VERSION 5.7 ;
BUSBITCHARS "[]" ;
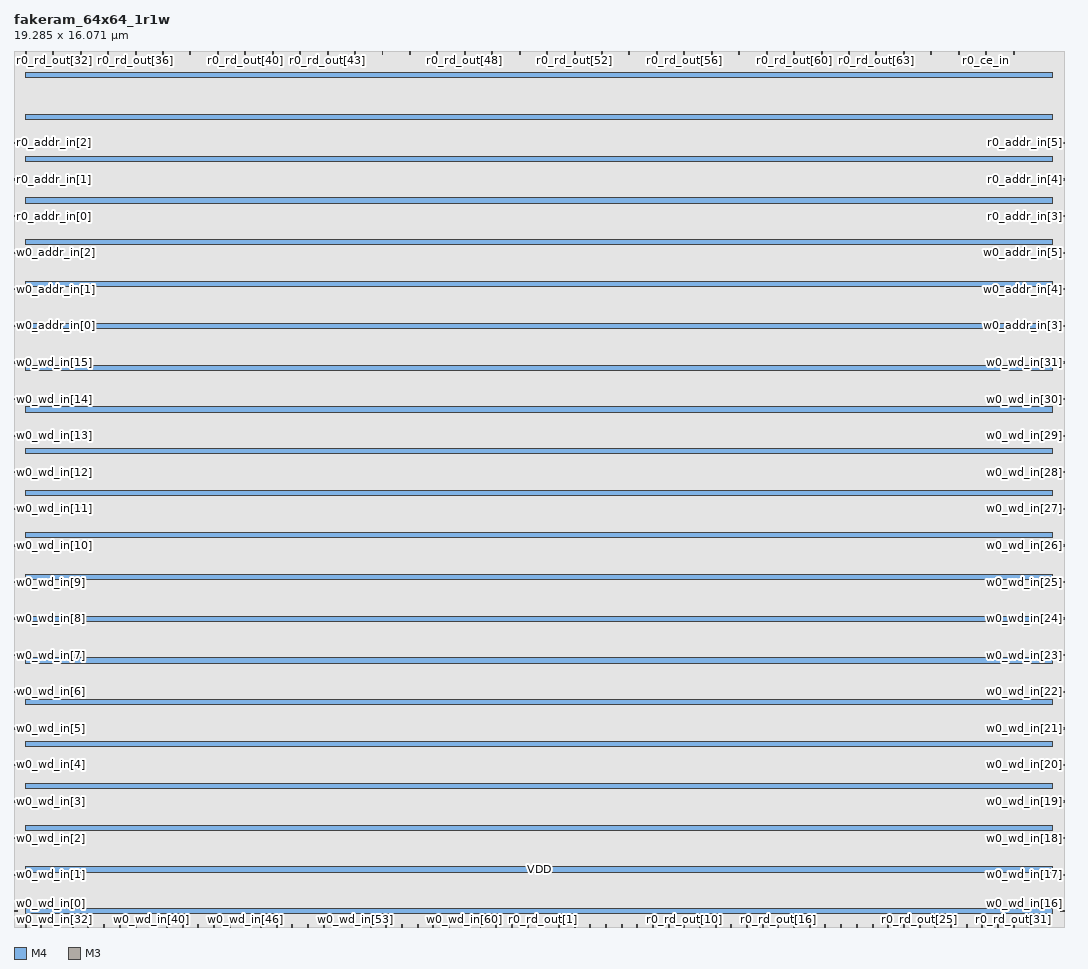
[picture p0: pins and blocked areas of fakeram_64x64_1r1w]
MACRO fakeram_64x64_1r1w
  FOREIGN fakeram_64x64_1r1w 0 0 ;
  SYMMETRY X Y R90 ;
  SIZE 19.285 BY 16.071 ;
  CLASS BLOCK ;
  PIN w0_wd_in[0]
    DIRECTION INPUT ;
    USE SIGNAL ;
    SHAPE ABUTMENT ;
    PORT
      LAYER M4 ;
      RECT 0.000 0.276 0.072 0.300 ;
    END
  END w0_wd_in[0]
  PIN w0_wd_in[1]
    DIRECTION INPUT ;
    USE SIGNAL ;
    SHAPE ABUTMENT ;
    PORT
      LAYER M4 ;
      RECT 0.000 0.948 0.072 0.972 ;
    END
  END w0_wd_in[1]
  PIN w0_wd_in[2]
    DIRECTION INPUT ;
    USE SIGNAL ;
    SHAPE ABUTMENT ;
    PORT
      LAYER M4 ;
      RECT 0.000 1.620 0.072 1.644 ;
    END
  END w0_wd_in[2]
  PIN w0_wd_in[3]
    DIRECTION INPUT ;
    USE SIGNAL ;
    SHAPE ABUTMENT ;
    PORT
      LAYER M4 ;
      RECT 0.000 2.292 0.072 2.316 ;
    END
  END w0_wd_in[3]
  PIN w0_wd_in[4]
    DIRECTION INPUT ;
    USE SIGNAL ;
    SHAPE ABUTMENT ;
    PORT
      LAYER M4 ;
      RECT 0.000 2.964 0.072 2.988 ;
    END
  END w0_wd_in[4]
  PIN w0_wd_in[5]
    DIRECTION INPUT ;
    USE SIGNAL ;
    SHAPE ABUTMENT ;
    PORT
      LAYER M4 ;
      RECT 0.000 3.636 0.072 3.660 ;
    END
  END w0_wd_in[5]
  PIN w0_wd_in[6]
    DIRECTION INPUT ;
    USE SIGNAL ;
    SHAPE ABUTMENT ;
    PORT
      LAYER M4 ;
      RECT 0.000 4.308 0.072 4.332 ;
    END
  END w0_wd_in[6]
  PIN w0_wd_in[7]
    DIRECTION INPUT ;
    USE SIGNAL ;
    SHAPE ABUTMENT ;
    PORT
      LAYER M4 ;
      RECT 0.000 4.980 0.072 5.004 ;
    END
  END w0_wd_in[7]
  PIN w0_wd_in[8]
    DIRECTION INPUT ;
    USE SIGNAL ;
    SHAPE ABUTMENT ;
    PORT
      LAYER M4 ;
      RECT 0.000 5.652 0.072 5.676 ;
    END
  END w0_wd_in[8]
  PIN w0_wd_in[9]
    DIRECTION INPUT ;
    USE SIGNAL ;
    SHAPE ABUTMENT ;
    PORT
      LAYER M4 ;
      RECT 0.000 6.324 0.072 6.348 ;
    END
  END w0_wd_in[9]
  PIN w0_wd_in[10]
    DIRECTION INPUT ;
    USE SIGNAL ;
    SHAPE ABUTMENT ;
    PORT
      LAYER M4 ;
      RECT 0.000 6.996 0.072 7.020 ;
    END
  END w0_wd_in[10]
  PIN w0_wd_in[11]
    DIRECTION INPUT ;
    USE SIGNAL ;
    SHAPE ABUTMENT ;
    PORT
      LAYER M4 ;
      RECT 0.000 7.668 0.072 7.692 ;
    END
  END w0_wd_in[11]
  PIN w0_wd_in[12]
    DIRECTION INPUT ;
    USE SIGNAL ;
    SHAPE ABUTMENT ;
    PORT
      LAYER M4 ;
      RECT 0.000 8.340 0.072 8.364 ;
    END
  END w0_wd_in[12]
  PIN w0_wd_in[13]
    DIRECTION INPUT ;
    USE SIGNAL ;
    SHAPE ABUTMENT ;
    PORT
      LAYER M4 ;
      RECT 0.000 9.012 0.072 9.036 ;
    END
  END w0_wd_in[13]
  PIN w0_wd_in[14]
    DIRECTION INPUT ;
    USE SIGNAL ;
    SHAPE ABUTMENT ;
    PORT
      LAYER M4 ;
      RECT 0.000 9.684 0.072 9.708 ;
    END
  END w0_wd_in[14]
  PIN w0_wd_in[15]
    DIRECTION INPUT ;
    USE SIGNAL ;
    SHAPE ABUTMENT ;
    PORT
      LAYER M4 ;
      RECT 0.000 10.356 0.072 10.380 ;
    END
  END w0_wd_in[15]
  PIN w0_wd_in[16]
    DIRECTION INPUT ;
    USE SIGNAL ;
    SHAPE ABUTMENT ;
    PORT
      LAYER M4 ;
      RECT 19.213 0.276 19.285 0.300 ;
    END
  END w0_wd_in[16]
  PIN w0_wd_in[17]
    DIRECTION INPUT ;
    USE SIGNAL ;
    SHAPE ABUTMENT ;
    PORT
      LAYER M4 ;
      RECT 19.213 0.948 19.285 0.972 ;
    END
  END w0_wd_in[17]
  PIN w0_wd_in[18]
    DIRECTION INPUT ;
    USE SIGNAL ;
    SHAPE ABUTMENT ;
    PORT
      LAYER M4 ;
      RECT 19.213 1.620 19.285 1.644 ;
    END
  END w0_wd_in[18]
  PIN w0_wd_in[19]
    DIRECTION INPUT ;
    USE SIGNAL ;
    SHAPE ABUTMENT ;
    PORT
      LAYER M4 ;
      RECT 19.213 2.292 19.285 2.316 ;
    END
  END w0_wd_in[19]
  PIN w0_wd_in[20]
    DIRECTION INPUT ;
    USE SIGNAL ;
    SHAPE ABUTMENT ;
    PORT
      LAYER M4 ;
      RECT 19.213 2.964 19.285 2.988 ;
    END
  END w0_wd_in[20]
  PIN w0_wd_in[21]
    DIRECTION INPUT ;
    USE SIGNAL ;
    SHAPE ABUTMENT ;
    PORT
      LAYER M4 ;
      RECT 19.213 3.636 19.285 3.660 ;
    END
  END w0_wd_in[21]
  PIN w0_wd_in[22]
    DIRECTION INPUT ;
    USE SIGNAL ;
    SHAPE ABUTMENT ;
    PORT
      LAYER M4 ;
      RECT 19.213 4.308 19.285 4.332 ;
    END
  END w0_wd_in[22]
  PIN w0_wd_in[23]
    DIRECTION INPUT ;
    USE SIGNAL ;
    SHAPE ABUTMENT ;
    PORT
      LAYER M4 ;
      RECT 19.213 4.980 19.285 5.004 ;
    END
  END w0_wd_in[23]
  PIN w0_wd_in[24]
    DIRECTION INPUT ;
    USE SIGNAL ;
    SHAPE ABUTMENT ;
    PORT
      LAYER M4 ;
      RECT 19.213 5.652 19.285 5.676 ;
    END
  END w0_wd_in[24]
  PIN w0_wd_in[25]
    DIRECTION INPUT ;
    USE SIGNAL ;
    SHAPE ABUTMENT ;
    PORT
      LAYER M4 ;
      RECT 19.213 6.324 19.285 6.348 ;
    END
  END w0_wd_in[25]
  PIN w0_wd_in[26]
    DIRECTION INPUT ;
    USE SIGNAL ;
    SHAPE ABUTMENT ;
    PORT
      LAYER M4 ;
      RECT 19.213 6.996 19.285 7.020 ;
    END
  END w0_wd_in[26]
  PIN w0_wd_in[27]
    DIRECTION INPUT ;
    USE SIGNAL ;
    SHAPE ABUTMENT ;
    PORT
      LAYER M4 ;
      RECT 19.213 7.668 19.285 7.692 ;
    END
  END w0_wd_in[27]
  PIN w0_wd_in[28]
    DIRECTION INPUT ;
    USE SIGNAL ;
    SHAPE ABUTMENT ;
    PORT
      LAYER M4 ;
      RECT 19.213 8.340 19.285 8.364 ;
    END
  END w0_wd_in[28]
  PIN w0_wd_in[29]
    DIRECTION INPUT ;
    USE SIGNAL ;
    SHAPE ABUTMENT ;
    PORT
      LAYER M4 ;
      RECT 19.213 9.012 19.285 9.036 ;
    END
  END w0_wd_in[29]
  PIN w0_wd_in[30]
    DIRECTION INPUT ;
    USE SIGNAL ;
    SHAPE ABUTMENT ;
    PORT
      LAYER M4 ;
      RECT 19.213 9.684 19.285 9.708 ;
    END
  END w0_wd_in[30]
  PIN w0_wd_in[31]
    DIRECTION INPUT ;
    USE SIGNAL ;
    SHAPE ABUTMENT ;
    PORT
      LAYER M4 ;
      RECT 19.213 10.356 19.285 10.380 ;
    END
  END w0_wd_in[31]
  PIN w0_wd_in[32]
    DIRECTION OUTPUT ;
    USE SIGNAL ;
    SHAPE ABUTMENT ;
    PORT
      LAYER M3 ;
      RECT 0.207 0.000 0.225 0.054 ;
    END
  END w0_wd_in[32]
  PIN w0_wd_in[33]
    DIRECTION OUTPUT ;
    USE SIGNAL ;
    SHAPE ABUTMENT ;
    PORT
      LAYER M3 ;
      RECT 0.495 0.000 0.513 0.054 ;
    END
  END w0_wd_in[33]
  PIN w0_wd_in[34]
    DIRECTION OUTPUT ;
    USE SIGNAL ;
    SHAPE ABUTMENT ;
    PORT
      LAYER M3 ;
      RECT 0.783 0.000 0.801 0.054 ;
    END
  END w0_wd_in[34]
  PIN w0_wd_in[35]
    DIRECTION OUTPUT ;
    USE SIGNAL ;
    SHAPE ABUTMENT ;
    PORT
      LAYER M3 ;
      RECT 1.071 0.000 1.089 0.054 ;
    END
  END w0_wd_in[35]
  PIN w0_wd_in[36]
    DIRECTION OUTPUT ;
    USE SIGNAL ;
    SHAPE ABUTMENT ;
    PORT
      LAYER M3 ;
      RECT 1.359 0.000 1.377 0.054 ;
    END
  END w0_wd_in[36]
  PIN w0_wd_in[37]
    DIRECTION OUTPUT ;
    USE SIGNAL ;
    SHAPE ABUTMENT ;
    PORT
      LAYER M3 ;
      RECT 1.647 0.000 1.665 0.054 ;
    END
  END w0_wd_in[37]
  PIN w0_wd_in[38]
    DIRECTION OUTPUT ;
    USE SIGNAL ;
    SHAPE ABUTMENT ;
    PORT
      LAYER M3 ;
      RECT 1.935 0.000 1.953 0.054 ;
    END
  END w0_wd_in[38]
  PIN w0_wd_in[39]
    DIRECTION OUTPUT ;
    USE SIGNAL ;
    SHAPE ABUTMENT ;
    PORT
      LAYER M3 ;
      RECT 2.223 0.000 2.241 0.054 ;
    END
  END w0_wd_in[39]
  PIN w0_wd_in[40]
    DIRECTION OUTPUT ;
    USE SIGNAL ;
    SHAPE ABUTMENT ;
    PORT
      LAYER M3 ;
      RECT 2.511 0.000 2.529 0.054 ;
    END
  END w0_wd_in[40]
  PIN w0_wd_in[41]
    DIRECTION OUTPUT ;
    USE SIGNAL ;
    SHAPE ABUTMENT ;
    PORT
      LAYER M3 ;
      RECT 2.799 0.000 2.817 0.054 ;
    END
  END w0_wd_in[41]
  PIN w0_wd_in[42]
    DIRECTION OUTPUT ;
    USE SIGNAL ;
    SHAPE ABUTMENT ;
    PORT
      LAYER M3 ;
      RECT 3.087 0.000 3.105 0.054 ;
    END
  END w0_wd_in[42]
  PIN w0_wd_in[43]
    DIRECTION OUTPUT ;
    USE SIGNAL ;
    SHAPE ABUTMENT ;
    PORT
      LAYER M3 ;
      RECT 3.375 0.000 3.393 0.054 ;
    END
  END w0_wd_in[43]
  PIN w0_wd_in[44]
    DIRECTION OUTPUT ;
    USE SIGNAL ;
    SHAPE ABUTMENT ;
    PORT
      LAYER M3 ;
      RECT 3.663 0.000 3.681 0.054 ;
    END
  END w0_wd_in[44]
  PIN w0_wd_in[45]
    DIRECTION OUTPUT ;
    USE SIGNAL ;
    SHAPE ABUTMENT ;
    PORT
      LAYER M3 ;
      RECT 3.951 0.000 3.969 0.054 ;
    END
  END w0_wd_in[45]
  PIN w0_wd_in[46]
    DIRECTION OUTPUT ;
    USE SIGNAL ;
    SHAPE ABUTMENT ;
    PORT
      LAYER M3 ;
      RECT 4.239 0.000 4.257 0.054 ;
    END
  END w0_wd_in[46]
  PIN w0_wd_in[47]
    DIRECTION OUTPUT ;
    USE SIGNAL ;
    SHAPE ABUTMENT ;
    PORT
      LAYER M3 ;
      RECT 4.527 0.000 4.545 0.054 ;
    END
  END w0_wd_in[47]
  PIN w0_wd_in[48]
    DIRECTION OUTPUT ;
    USE SIGNAL ;
    SHAPE ABUTMENT ;
    PORT
      LAYER M3 ;
      RECT 4.815 0.000 4.833 0.054 ;
    END
  END w0_wd_in[48]
  PIN w0_wd_in[49]
    DIRECTION OUTPUT ;
    USE SIGNAL ;
    SHAPE ABUTMENT ;
    PORT
      LAYER M3 ;
      RECT 5.103 0.000 5.121 0.054 ;
    END
  END w0_wd_in[49]
  PIN w0_wd_in[50]
    DIRECTION OUTPUT ;
    USE SIGNAL ;
    SHAPE ABUTMENT ;
    PORT
      LAYER M3 ;
      RECT 5.391 0.000 5.409 0.054 ;
    END
  END w0_wd_in[50]
  PIN w0_wd_in[51]
    DIRECTION OUTPUT ;
    USE SIGNAL ;
    SHAPE ABUTMENT ;
    PORT
      LAYER M3 ;
      RECT 5.679 0.000 5.697 0.054 ;
    END
  END w0_wd_in[51]
  PIN w0_wd_in[52]
    DIRECTION OUTPUT ;
    USE SIGNAL ;
    SHAPE ABUTMENT ;
    PORT
      LAYER M3 ;
      RECT 5.967 0.000 5.985 0.054 ;
    END
  END w0_wd_in[52]
  PIN w0_wd_in[53]
    DIRECTION OUTPUT ;
    USE SIGNAL ;
    SHAPE ABUTMENT ;
    PORT
      LAYER M3 ;
      RECT 6.255 0.000 6.273 0.054 ;
    END
  END w0_wd_in[53]
  PIN w0_wd_in[54]
    DIRECTION OUTPUT ;
    USE SIGNAL ;
    SHAPE ABUTMENT ;
    PORT
      LAYER M3 ;
      RECT 6.543 0.000 6.561 0.054 ;
    END
  END w0_wd_in[54]
  PIN w0_wd_in[55]
    DIRECTION OUTPUT ;
    USE SIGNAL ;
    SHAPE ABUTMENT ;
    PORT
      LAYER M3 ;
      RECT 6.831 0.000 6.849 0.054 ;
    END
  END w0_wd_in[55]
  PIN w0_wd_in[56]
    DIRECTION OUTPUT ;
    USE SIGNAL ;
    SHAPE ABUTMENT ;
    PORT
      LAYER M3 ;
      RECT 7.119 0.000 7.137 0.054 ;
    END
  END w0_wd_in[56]
  PIN w0_wd_in[57]
    DIRECTION OUTPUT ;
    USE SIGNAL ;
    SHAPE ABUTMENT ;
    PORT
      LAYER M3 ;
      RECT 7.407 0.000 7.425 0.054 ;
    END
  END w0_wd_in[57]
  PIN w0_wd_in[58]
    DIRECTION OUTPUT ;
    USE SIGNAL ;
    SHAPE ABUTMENT ;
    PORT
      LAYER M3 ;
      RECT 7.695 0.000 7.713 0.054 ;
    END
  END w0_wd_in[58]
  PIN w0_wd_in[59]
    DIRECTION OUTPUT ;
    USE SIGNAL ;
    SHAPE ABUTMENT ;
    PORT
      LAYER M3 ;
      RECT 7.983 0.000 8.001 0.054 ;
    END
  END w0_wd_in[59]
  PIN w0_wd_in[60]
    DIRECTION OUTPUT ;
    USE SIGNAL ;
    SHAPE ABUTMENT ;
    PORT
      LAYER M3 ;
      RECT 8.271 0.000 8.289 0.054 ;
    END
  END w0_wd_in[60]
  PIN w0_wd_in[61]
    DIRECTION OUTPUT ;
    USE SIGNAL ;
    SHAPE ABUTMENT ;
    PORT
      LAYER M3 ;
      RECT 8.559 0.000 8.577 0.054 ;
    END
  END w0_wd_in[61]
  PIN w0_wd_in[62]
    DIRECTION OUTPUT ;
    USE SIGNAL ;
    SHAPE ABUTMENT ;
    PORT
      LAYER M3 ;
      RECT 8.847 0.000 8.865 0.054 ;
    END
  END w0_wd_in[62]
  PIN w0_wd_in[63]
    DIRECTION OUTPUT ;
    USE SIGNAL ;
    SHAPE ABUTMENT ;
    PORT
      LAYER M3 ;
      RECT 9.135 0.000 9.153 0.054 ;
    END
  END w0_wd_in[63]
  PIN r0_rd_out[0]
    DIRECTION OUTPUT ;
    USE SIGNAL ;
    SHAPE ABUTMENT ;
    PORT
      LAYER M3 ;
      RECT 9.423 0.000 9.441 0.054 ;
    END
  END r0_rd_out[0]
  PIN r0_rd_out[1]
    DIRECTION OUTPUT ;
    USE SIGNAL ;
    SHAPE ABUTMENT ;
    PORT
      LAYER M3 ;
      RECT 9.711 0.000 9.729 0.054 ;
    END
  END r0_rd_out[1]
  PIN r0_rd_out[2]
    DIRECTION OUTPUT ;
    USE SIGNAL ;
    SHAPE ABUTMENT ;
    PORT
      LAYER M3 ;
      RECT 9.999 0.000 10.017 0.054 ;
    END
  END r0_rd_out[2]
  PIN r0_rd_out[3]
    DIRECTION OUTPUT ;
    USE SIGNAL ;
    SHAPE ABUTMENT ;
    PORT
      LAYER M3 ;
      RECT 10.287 0.000 10.305 0.054 ;
    END
  END r0_rd_out[3]
  PIN r0_rd_out[4]
    DIRECTION OUTPUT ;
    USE SIGNAL ;
    SHAPE ABUTMENT ;
    PORT
      LAYER M3 ;
      RECT 10.575 0.000 10.593 0.054 ;
    END
  END r0_rd_out[4]
  PIN r0_rd_out[5]
    DIRECTION OUTPUT ;
    USE SIGNAL ;
    SHAPE ABUTMENT ;
    PORT
      LAYER M3 ;
      RECT 10.863 0.000 10.881 0.054 ;
    END
  END r0_rd_out[5]
  PIN r0_rd_out[6]
    DIRECTION OUTPUT ;
    USE SIGNAL ;
    SHAPE ABUTMENT ;
    PORT
      LAYER M3 ;
      RECT 11.151 0.000 11.169 0.054 ;
    END
  END r0_rd_out[6]
  PIN r0_rd_out[7]
    DIRECTION OUTPUT ;
    USE SIGNAL ;
    SHAPE ABUTMENT ;
    PORT
      LAYER M3 ;
      RECT 11.439 0.000 11.457 0.054 ;
    END
  END r0_rd_out[7]
  PIN r0_rd_out[8]
    DIRECTION OUTPUT ;
    USE SIGNAL ;
    SHAPE ABUTMENT ;
    PORT
      LAYER M3 ;
      RECT 11.727 0.000 11.745 0.054 ;
    END
  END r0_rd_out[8]
  PIN r0_rd_out[9]
    DIRECTION OUTPUT ;
    USE SIGNAL ;
    SHAPE ABUTMENT ;
    PORT
      LAYER M3 ;
      RECT 12.015 0.000 12.033 0.054 ;
    END
  END r0_rd_out[9]
  PIN r0_rd_out[10]
    DIRECTION OUTPUT ;
    USE SIGNAL ;
    SHAPE ABUTMENT ;
    PORT
      LAYER M3 ;
      RECT 12.303 0.000 12.321 0.054 ;
    END
  END r0_rd_out[10]
  PIN r0_rd_out[11]
    DIRECTION OUTPUT ;
    USE SIGNAL ;
    SHAPE ABUTMENT ;
    PORT
      LAYER M3 ;
      RECT 12.591 0.000 12.609 0.054 ;
    END
  END r0_rd_out[11]
  PIN r0_rd_out[12]
    DIRECTION OUTPUT ;
    USE SIGNAL ;
    SHAPE ABUTMENT ;
    PORT
      LAYER M3 ;
      RECT 12.879 0.000 12.897 0.054 ;
    END
  END r0_rd_out[12]
  PIN r0_rd_out[13]
    DIRECTION OUTPUT ;
    USE SIGNAL ;
    SHAPE ABUTMENT ;
    PORT
      LAYER M3 ;
      RECT 13.167 0.000 13.185 0.054 ;
    END
  END r0_rd_out[13]
  PIN r0_rd_out[14]
    DIRECTION OUTPUT ;
    USE SIGNAL ;
    SHAPE ABUTMENT ;
    PORT
      LAYER M3 ;
      RECT 13.455 0.000 13.473 0.054 ;
    END
  END r0_rd_out[14]
  PIN r0_rd_out[15]
    DIRECTION OUTPUT ;
    USE SIGNAL ;
    SHAPE ABUTMENT ;
    PORT
      LAYER M3 ;
      RECT 13.743 0.000 13.761 0.054 ;
    END
  END r0_rd_out[15]
  PIN r0_rd_out[16]
    DIRECTION OUTPUT ;
    USE SIGNAL ;
    SHAPE ABUTMENT ;
    PORT
      LAYER M3 ;
      RECT 14.031 0.000 14.049 0.054 ;
    END
  END r0_rd_out[16]
  PIN r0_rd_out[17]
    DIRECTION OUTPUT ;
    USE SIGNAL ;
    SHAPE ABUTMENT ;
    PORT
      LAYER M3 ;
      RECT 14.319 0.000 14.337 0.054 ;
    END
  END r0_rd_out[17]
  PIN r0_rd_out[18]
    DIRECTION OUTPUT ;
    USE SIGNAL ;
    SHAPE ABUTMENT ;
    PORT
      LAYER M3 ;
      RECT 14.607 0.000 14.625 0.054 ;
    END
  END r0_rd_out[18]
  PIN r0_rd_out[19]
    DIRECTION OUTPUT ;
    USE SIGNAL ;
    SHAPE ABUTMENT ;
    PORT
      LAYER M3 ;
      RECT 14.895 0.000 14.913 0.054 ;
    END
  END r0_rd_out[19]
  PIN r0_rd_out[20]
    DIRECTION OUTPUT ;
    USE SIGNAL ;
    SHAPE ABUTMENT ;
    PORT
      LAYER M3 ;
      RECT 15.183 0.000 15.201 0.054 ;
    END
  END r0_rd_out[20]
  PIN r0_rd_out[21]
    DIRECTION OUTPUT ;
    USE SIGNAL ;
    SHAPE ABUTMENT ;
    PORT
      LAYER M3 ;
      RECT 15.471 0.000 15.489 0.054 ;
    END
  END r0_rd_out[21]
  PIN r0_rd_out[22]
    DIRECTION OUTPUT ;
    USE SIGNAL ;
    SHAPE ABUTMENT ;
    PORT
      LAYER M3 ;
      RECT 15.759 0.000 15.777 0.054 ;
    END
  END r0_rd_out[22]
  PIN r0_rd_out[23]
    DIRECTION OUTPUT ;
    USE SIGNAL ;
    SHAPE ABUTMENT ;
    PORT
      LAYER M3 ;
      RECT 16.047 0.000 16.065 0.054 ;
    END
  END r0_rd_out[23]
  PIN r0_rd_out[24]
    DIRECTION OUTPUT ;
    USE SIGNAL ;
    SHAPE ABUTMENT ;
    PORT
      LAYER M3 ;
      RECT 16.335 0.000 16.353 0.054 ;
    END
  END r0_rd_out[24]
  PIN r0_rd_out[25]
    DIRECTION OUTPUT ;
    USE SIGNAL ;
    SHAPE ABUTMENT ;
    PORT
      LAYER M3 ;
      RECT 16.623 0.000 16.641 0.054 ;
    END
  END r0_rd_out[25]
  PIN r0_rd_out[26]
    DIRECTION OUTPUT ;
    USE SIGNAL ;
    SHAPE ABUTMENT ;
    PORT
      LAYER M3 ;
      RECT 16.911 0.000 16.929 0.054 ;
    END
  END r0_rd_out[26]
  PIN r0_rd_out[27]
    DIRECTION OUTPUT ;
    USE SIGNAL ;
    SHAPE ABUTMENT ;
    PORT
      LAYER M3 ;
      RECT 17.199 0.000 17.217 0.054 ;
    END
  END r0_rd_out[27]
  PIN r0_rd_out[28]
    DIRECTION OUTPUT ;
    USE SIGNAL ;
    SHAPE ABUTMENT ;
    PORT
      LAYER M3 ;
      RECT 17.487 0.000 17.505 0.054 ;
    END
  END r0_rd_out[28]
  PIN r0_rd_out[29]
    DIRECTION OUTPUT ;
    USE SIGNAL ;
    SHAPE ABUTMENT ;
    PORT
      LAYER M3 ;
      RECT 17.775 0.000 17.793 0.054 ;
    END
  END r0_rd_out[29]
  PIN r0_rd_out[30]
    DIRECTION OUTPUT ;
    USE SIGNAL ;
    SHAPE ABUTMENT ;
    PORT
      LAYER M3 ;
      RECT 18.063 0.000 18.081 0.054 ;
    END
  END r0_rd_out[30]
  PIN r0_rd_out[31]
    DIRECTION OUTPUT ;
    USE SIGNAL ;
    SHAPE ABUTMENT ;
    PORT
      LAYER M3 ;
      RECT 18.351 0.000 18.369 0.054 ;
    END
  END r0_rd_out[31]
  PIN r0_rd_out[32]
    DIRECTION OUTPUT ;
    USE SIGNAL ;
    SHAPE ABUTMENT ;
    PORT
      LAYER M3 ;
      RECT 0.207 16.017 0.225 16.071 ;
    END
  END r0_rd_out[32]
  PIN r0_rd_out[33]
    DIRECTION OUTPUT ;
    USE SIGNAL ;
    SHAPE ABUTMENT ;
    PORT
      LAYER M3 ;
      RECT 0.711 16.017 0.729 16.071 ;
    END
  END r0_rd_out[33]
  PIN r0_rd_out[34]
    DIRECTION OUTPUT ;
    USE SIGNAL ;
    SHAPE ABUTMENT ;
    PORT
      LAYER M3 ;
      RECT 1.215 16.017 1.233 16.071 ;
    END
  END r0_rd_out[34]
  PIN r0_rd_out[35]
    DIRECTION OUTPUT ;
    USE SIGNAL ;
    SHAPE ABUTMENT ;
    PORT
      LAYER M3 ;
      RECT 1.719 16.017 1.737 16.071 ;
    END
  END r0_rd_out[35]
  PIN r0_rd_out[36]
    DIRECTION OUTPUT ;
    USE SIGNAL ;
    SHAPE ABUTMENT ;
    PORT
      LAYER M3 ;
      RECT 2.223 16.017 2.241 16.071 ;
    END
  END r0_rd_out[36]
  PIN r0_rd_out[37]
    DIRECTION OUTPUT ;
    USE SIGNAL ;
    SHAPE ABUTMENT ;
    PORT
      LAYER M3 ;
      RECT 2.727 16.017 2.745 16.071 ;
    END
  END r0_rd_out[37]
  PIN r0_rd_out[38]
    DIRECTION OUTPUT ;
    USE SIGNAL ;
    SHAPE ABUTMENT ;
    PORT
      LAYER M3 ;
      RECT 3.231 16.017 3.249 16.071 ;
    END
  END r0_rd_out[38]
  PIN r0_rd_out[39]
    DIRECTION OUTPUT ;
    USE SIGNAL ;
    SHAPE ABUTMENT ;
    PORT
      LAYER M3 ;
      RECT 3.735 16.017 3.753 16.071 ;
    END
  END r0_rd_out[39]
  PIN r0_rd_out[40]
    DIRECTION OUTPUT ;
    USE SIGNAL ;
    SHAPE ABUTMENT ;
    PORT
      LAYER M3 ;
      RECT 4.239 16.017 4.257 16.071 ;
    END
  END r0_rd_out[40]
  PIN r0_rd_out[41]
    DIRECTION OUTPUT ;
    USE SIGNAL ;
    SHAPE ABUTMENT ;
    PORT
      LAYER M3 ;
      RECT 4.743 16.017 4.761 16.071 ;
    END
  END r0_rd_out[41]
  PIN r0_rd_out[42]
    DIRECTION OUTPUT ;
    USE SIGNAL ;
    SHAPE ABUTMENT ;
    PORT
      LAYER M3 ;
      RECT 5.247 16.017 5.265 16.071 ;
    END
  END r0_rd_out[42]
  PIN r0_rd_out[43]
    DIRECTION OUTPUT ;
    USE SIGNAL ;
    SHAPE ABUTMENT ;
    PORT
      LAYER M3 ;
      RECT 5.751 16.017 5.769 16.071 ;
    END
  END r0_rd_out[43]
  PIN r0_rd_out[44]
    DIRECTION OUTPUT ;
    USE SIGNAL ;
    SHAPE ABUTMENT ;
    PORT
      LAYER M3 ;
      RECT 6.255 16.017 6.273 16.071 ;
    END
  END r0_rd_out[44]
  PIN r0_rd_out[45]
    DIRECTION OUTPUT ;
    USE SIGNAL ;
    SHAPE ABUTMENT ;
    PORT
      LAYER M3 ;
      RECT 6.759 16.017 6.777 16.071 ;
    END
  END r0_rd_out[45]
  PIN r0_rd_out[46]
    DIRECTION OUTPUT ;
    USE SIGNAL ;
    SHAPE ABUTMENT ;
    PORT
      LAYER M3 ;
      RECT 7.263 16.017 7.281 16.071 ;
    END
  END r0_rd_out[46]
  PIN r0_rd_out[47]
    DIRECTION OUTPUT ;
    USE SIGNAL ;
    SHAPE ABUTMENT ;
    PORT
      LAYER M3 ;
      RECT 7.767 16.017 7.785 16.071 ;
    END
  END r0_rd_out[47]
  PIN r0_rd_out[48]
    DIRECTION OUTPUT ;
    USE SIGNAL ;
    SHAPE ABUTMENT ;
    PORT
      LAYER M3 ;
      RECT 8.271 16.017 8.289 16.071 ;
    END
  END r0_rd_out[48]
  PIN r0_rd_out[49]
    DIRECTION OUTPUT ;
    USE SIGNAL ;
    SHAPE ABUTMENT ;
    PORT
      LAYER M3 ;
      RECT 8.775 16.017 8.793 16.071 ;
    END
  END r0_rd_out[49]
  PIN r0_rd_out[50]
    DIRECTION OUTPUT ;
    USE SIGNAL ;
    SHAPE ABUTMENT ;
    PORT
      LAYER M3 ;
      RECT 9.279 16.017 9.297 16.071 ;
    END
  END r0_rd_out[50]
  PIN r0_rd_out[51]
    DIRECTION OUTPUT ;
    USE SIGNAL ;
    SHAPE ABUTMENT ;
    PORT
      LAYER M3 ;
      RECT 9.783 16.017 9.801 16.071 ;
    END
  END r0_rd_out[51]
  PIN r0_rd_out[52]
    DIRECTION OUTPUT ;
    USE SIGNAL ;
    SHAPE ABUTMENT ;
    PORT
      LAYER M3 ;
      RECT 10.287 16.017 10.305 16.071 ;
    END
  END r0_rd_out[52]
  PIN r0_rd_out[53]
    DIRECTION OUTPUT ;
    USE SIGNAL ;
    SHAPE ABUTMENT ;
    PORT
      LAYER M3 ;
      RECT 10.791 16.017 10.809 16.071 ;
    END
  END r0_rd_out[53]
  PIN r0_rd_out[54]
    DIRECTION OUTPUT ;
    USE SIGNAL ;
    SHAPE ABUTMENT ;
    PORT
      LAYER M3 ;
      RECT 11.295 16.017 11.313 16.071 ;
    END
  END r0_rd_out[54]
  PIN r0_rd_out[55]
    DIRECTION OUTPUT ;
    USE SIGNAL ;
    SHAPE ABUTMENT ;
    PORT
      LAYER M3 ;
      RECT 11.799 16.017 11.817 16.071 ;
    END
  END r0_rd_out[55]
  PIN r0_rd_out[56]
    DIRECTION OUTPUT ;
    USE SIGNAL ;
    SHAPE ABUTMENT ;
    PORT
      LAYER M3 ;
      RECT 12.303 16.017 12.321 16.071 ;
    END
  END r0_rd_out[56]
  PIN r0_rd_out[57]
    DIRECTION OUTPUT ;
    USE SIGNAL ;
    SHAPE ABUTMENT ;
    PORT
      LAYER M3 ;
      RECT 12.807 16.017 12.825 16.071 ;
    END
  END r0_rd_out[57]
  PIN r0_rd_out[58]
    DIRECTION OUTPUT ;
    USE SIGNAL ;
    SHAPE ABUTMENT ;
    PORT
      LAYER M3 ;
      RECT 13.311 16.017 13.329 16.071 ;
    END
  END r0_rd_out[58]
  PIN r0_rd_out[59]
    DIRECTION OUTPUT ;
    USE SIGNAL ;
    SHAPE ABUTMENT ;
    PORT
      LAYER M3 ;
      RECT 13.815 16.017 13.833 16.071 ;
    END
  END r0_rd_out[59]
  PIN r0_rd_out[60]
    DIRECTION OUTPUT ;
    USE SIGNAL ;
    SHAPE ABUTMENT ;
    PORT
      LAYER M3 ;
      RECT 14.319 16.017 14.337 16.071 ;
    END
  END r0_rd_out[60]
  PIN r0_rd_out[61]
    DIRECTION OUTPUT ;
    USE SIGNAL ;
    SHAPE ABUTMENT ;
    PORT
      LAYER M3 ;
      RECT 14.823 16.017 14.841 16.071 ;
    END
  END r0_rd_out[61]
  PIN r0_rd_out[62]
    DIRECTION OUTPUT ;
    USE SIGNAL ;
    SHAPE ABUTMENT ;
    PORT
      LAYER M3 ;
      RECT 15.327 16.017 15.345 16.071 ;
    END
  END r0_rd_out[62]
  PIN r0_rd_out[63]
    DIRECTION OUTPUT ;
    USE SIGNAL ;
    SHAPE ABUTMENT ;
    PORT
      LAYER M3 ;
      RECT 15.831 16.017 15.849 16.071 ;
    END
  END r0_rd_out[63]
  PIN w0_addr_in[0]
    DIRECTION INPUT ;
    USE SIGNAL ;
    SHAPE ABUTMENT ;
    PORT
      LAYER M4 ;
      RECT 0.000 11.028 0.072 11.052 ;
    END
  END w0_addr_in[0]
  PIN w0_addr_in[1]
    DIRECTION INPUT ;
    USE SIGNAL ;
    SHAPE ABUTMENT ;
    PORT
      LAYER M4 ;
      RECT 0.000 11.700 0.072 11.724 ;
    END
  END w0_addr_in[1]
  PIN w0_addr_in[2]
    DIRECTION INPUT ;
    USE SIGNAL ;
    SHAPE ABUTMENT ;
    PORT
      LAYER M4 ;
      RECT 0.000 12.372 0.072 12.396 ;
    END
  END w0_addr_in[2]
  PIN w0_addr_in[3]
    DIRECTION INPUT ;
    USE SIGNAL ;
    SHAPE ABUTMENT ;
    PORT
      LAYER M4 ;
      RECT 19.213 11.028 19.285 11.052 ;
    END
  END w0_addr_in[3]
  PIN w0_addr_in[4]
    DIRECTION INPUT ;
    USE SIGNAL ;
    SHAPE ABUTMENT ;
    PORT
      LAYER M4 ;
      RECT 19.213 11.700 19.285 11.724 ;
    END
  END w0_addr_in[4]
  PIN w0_addr_in[5]
    DIRECTION INPUT ;
    USE SIGNAL ;
    SHAPE ABUTMENT ;
    PORT
      LAYER M4 ;
      RECT 19.213 12.372 19.285 12.396 ;
    END
  END w0_addr_in[5]
  PIN r0_addr_in[0]
    DIRECTION INPUT ;
    USE SIGNAL ;
    SHAPE ABUTMENT ;
    PORT
      LAYER M4 ;
      RECT 0.000 13.044 0.072 13.068 ;
    END
  END r0_addr_in[0]
  PIN r0_addr_in[1]
    DIRECTION INPUT ;
    USE SIGNAL ;
    SHAPE ABUTMENT ;
    PORT
      LAYER M4 ;
      RECT 0.000 13.716 0.072 13.740 ;
    END
  END r0_addr_in[1]
  PIN r0_addr_in[2]
    DIRECTION INPUT ;
    USE SIGNAL ;
    SHAPE ABUTMENT ;
    PORT
      LAYER M4 ;
      RECT 0.000 14.388 0.072 14.412 ;
    END
  END r0_addr_in[2]
  PIN r0_addr_in[3]
    DIRECTION INPUT ;
    USE SIGNAL ;
    SHAPE ABUTMENT ;
    PORT
      LAYER M4 ;
      RECT 19.213 13.044 19.285 13.068 ;
    END
  END r0_addr_in[3]
  PIN r0_addr_in[4]
    DIRECTION INPUT ;
    USE SIGNAL ;
    SHAPE ABUTMENT ;
    PORT
      LAYER M4 ;
      RECT 19.213 13.716 19.285 13.740 ;
    END
  END r0_addr_in[4]
  PIN r0_addr_in[5]
    DIRECTION INPUT ;
    USE SIGNAL ;
    SHAPE ABUTMENT ;
    PORT
      LAYER M4 ;
      RECT 19.213 14.388 19.285 14.412 ;
    END
  END r0_addr_in[5]
  PIN w0_we_in
    DIRECTION INPUT ;
    USE SIGNAL ;
    SHAPE ABUTMENT ;
    PORT
      LAYER M3 ;
      RECT 16.335 16.017 16.353 16.071 ;
    END
  END w0_we_in
  PIN w0_ce_in
    DIRECTION INPUT ;
    USE SIGNAL ;
    SHAPE ABUTMENT ;
    PORT
      LAYER M3 ;
      RECT 16.839 16.017 16.857 16.071 ;
    END
  END w0_ce_in
  PIN w0_clk
    DIRECTION INPUT ;
    USE SIGNAL ;
    SHAPE ABUTMENT ;
    PORT
      LAYER M3 ;
      RECT 17.343 16.017 17.361 16.071 ;
    END
  END w0_clk
  PIN r0_ce_in
    DIRECTION INPUT ;
    USE SIGNAL ;
    SHAPE ABUTMENT ;
    PORT
      LAYER M3 ;
      RECT 17.847 16.017 17.865 16.071 ;
    END
  END r0_ce_in
  PIN r0_clk
    DIRECTION INPUT ;
    USE SIGNAL ;
    SHAPE ABUTMENT ;
    PORT
      LAYER M3 ;
      RECT 18.351 16.017 18.369 16.071 ;
    END
  END r0_clk
  PIN VSS
    DIRECTION INOUT ;
    USE GROUND ;
    PORT
      LAYER M4 ;
      RECT 0.216 0.240 19.069 0.336 ;
      RECT 0.216 1.008 19.069 1.104 ;
      RECT 0.216 1.776 19.069 1.872 ;
      RECT 0.216 2.544 19.069 2.640 ;
      RECT 0.216 3.312 19.069 3.408 ;
      RECT 0.216 4.080 19.069 4.176 ;
      RECT 0.216 4.848 19.069 4.944 ;
      RECT 0.216 5.616 19.069 5.712 ;
      RECT 0.216 6.384 19.069 6.480 ;
      RECT 0.216 7.152 19.069 7.248 ;
      RECT 0.216 7.920 19.069 8.016 ;
      RECT 0.216 8.688 19.069 8.784 ;
      RECT 0.216 9.456 19.069 9.552 ;
      RECT 0.216 10.224 19.069 10.320 ;
      RECT 0.216 10.992 19.069 11.088 ;
      RECT 0.216 11.760 19.069 11.856 ;
      RECT 0.216 12.528 19.069 12.624 ;
      RECT 0.216 13.296 19.069 13.392 ;
      RECT 0.216 14.064 19.069 14.160 ;
      RECT 0.216 14.832 19.069 14.928 ;
      RECT 0.216 15.600 19.069 15.696 ;
    END
  END VSS
  PIN VDD
    DIRECTION INOUT ;
    USE POWER ;
    PORT
      LAYER M4 ;
      RECT 0.216 0.240 19.069 0.336 ;
      RECT 0.216 1.008 19.069 1.104 ;
      RECT 0.216 1.776 19.069 1.872 ;
      RECT 0.216 2.544 19.069 2.640 ;
      RECT 0.216 3.312 19.069 3.408 ;
      RECT 0.216 4.080 19.069 4.176 ;
      RECT 0.216 4.848 19.069 4.944 ;
      RECT 0.216 5.616 19.069 5.712 ;
      RECT 0.216 6.384 19.069 6.480 ;
      RECT 0.216 7.152 19.069 7.248 ;
      RECT 0.216 7.920 19.069 8.016 ;
      RECT 0.216 8.688 19.069 8.784 ;
      RECT 0.216 9.456 19.069 9.552 ;
      RECT 0.216 10.224 19.069 10.320 ;
      RECT 0.216 10.992 19.069 11.088 ;
      RECT 0.216 11.760 19.069 11.856 ;
      RECT 0.216 12.528 19.069 12.624 ;
      RECT 0.216 13.296 19.069 13.392 ;
      RECT 0.216 14.064 19.069 14.160 ;
      RECT 0.216 14.832 19.069 14.928 ;
      RECT 0.216 15.600 19.069 15.696 ;
    END
  END VDD
  OBS
    LAYER M1 ;
    RECT 0 0 19.285 16.071 ;
    LAYER M2 ;
    RECT 0 0 19.285 16.071 ;
    LAYER M3 ;
    RECT 0 0 19.285 16.071 ;
    LAYER M4 ;
    RECT 0 0 19.285 16.071 ;
  END
END fakeram_64x64_1r1w

END LIBRARY
